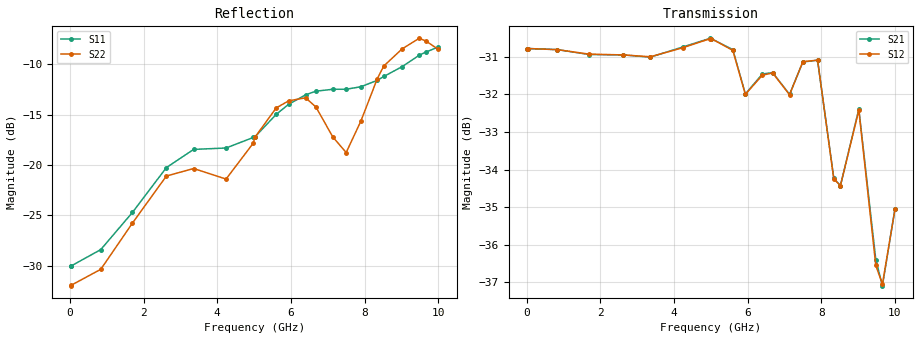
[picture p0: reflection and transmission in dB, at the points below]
! Integrated Device Technology
! Corporate Headquarters
! 6024 Silver Creek Valley Road
! San Jose, CA 95138  USA
! Phone:  1-408-284-8200
! Toll Free:  1-800-223-1366
! Webpage:  http://www.idt.com/
! Timing and RF Division
! 515 Groton Road, Suite 102
! Westford, MA 01886-6024
! Device:  F1958
! Description: 7-bit 0.25 dB Digital Step Attenuator
! Frequency:  0.001 -  6.000 GHz
! Package:  4x4 mm Thin QFN Plastic Package: 24 pin
! Ports:  2 RF, 12 DC
!  Pin  1  = D0
!  Pin  2  = VDD
!  Pin  3  = VMODE
!  Pin  4  = GND
!  Pin  5  = RF1  =  Port 1
!  Pin  6  = GND
!  Pin  7  = GND
!  Pin  8  = GND
!  Pin  9  = GND
!  Pin 10  = GND
!  Pin 11  = GND
!  Pin 12  = GND
!  Pin 13  = GND
!  Pin 14  = RF2  =  Port 2
!  Pin 15  = GND
!  Pin 16  = LE
!  Pin 17  = CLK
!  Pin 18  = DATA
!  Pin 19  = D6
!  Pin 20  = D5
!  Pin 21  = D4
!  Pin 22  = D3
!  Pin 23  = D2
!  Pin 24  = D1
! State:  120
! Atten State:  30.00 dB
! Voltage:  +3.30 Volts
! Current:  0.258 mA
! Data:  The device was measured on a F1958 evaluation board which has
!  individual transmission lines to the RF pins.  Data was collected
!  using a calibrated network analyzer.  The evaluation board was
!  de-embedded using Automatic Fixture Removal (AFR).
!  The reference plane is the edge of the package pin.
! Misc:
!  Action Tracker AT0419
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# GHz S dB R 50
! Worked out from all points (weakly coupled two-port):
!   500 points, 20 MHz to 10 GHz, reference 50 ohm
!   highest |S21| = -30.51 dB at 4.98 GHz (marker M1); lowest = -37.1 dB at 9.66 GHz (marker M2)
!   lowest |S11| = -30.0 dB at 40 MHz (marker M3), VSWR 1.07, Z = 46.9 - j0.0458 ohm
!   |S11| at or under -10 dB: start of sweep to 9.054 GHz
!   |S22| runs from -32.2 to -7.4 dB; largest |S21 - S12| = 0.00039
!   S11 on the Smith chart (normalised r, x): 20 MHz: 0.94, -0.00; 6.4 GHz: 0.67, +0.17; 10 GHz: 0.67, +0.60
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0.02  -30.01 -178.9  -30.80 -0.2  -30.80 -0.1  -32.00 -178.8
0.04  -30.03 -179.1  -30.78 -0.3  -30.78 -0.3  -31.95 -178.4
0.84  -28.41 171.8  -30.81 -9.4  -30.81 -9.4  -30.37 172.9
1.7  -24.71 171.9  -30.94 -18.5  -30.93 -18.5  -25.77 171.9
2.62  -20.26 177.6  -30.95 -28.4  -30.95 -28.4  -21.10 -179.1
3.36  -18.45 -175.3  -31.01 -36.8  -31.00 -37.0  -20.35 -169.2
4.24  -18.31 -178.8  -30.74 -46.2  -30.76 -46.3  -21.40 169.3
4.98  -17.26 162.1  -30.51 -55.4  -30.52 -55.4  -17.82 138.3
5.02  -17.22 161.1  -30.52 -56.2  -30.52 -56.2  -17.26 138.7
5.6  -14.97 151.1  -30.81 -64.8  -30.83 -64.8  -14.33 140.4
5.94  -13.96 148.5  -31.99 -68.4  -32.00 -68.4  -13.62 148.7
6.4  -13.02 147.9  -31.46 -73.6  -31.49 -73.5  -13.32 155.6
6.68  -12.66 146.7  -31.42 -76.1  -31.43 -76.1  -14.24 157.4
7.14  -12.47 142.7  -32.00 -81.2  -32.01 -81.1  -17.23 151.5
7.5  -12.47 138.2  -31.14 -84.7  -31.13 -84.6  -18.76 120.0
7.9  -12.22 128.8  -31.09 -100.4  -31.09 -100.5  -15.63 89.8
8.34  -11.59 118.8  -34.23 -106.0  -34.25 -106.1  -11.46 84.4
8.52  -11.20 115.5  -34.43 -97.5  -34.43 -97.7  -10.16 87.7
9.02  -10.22 107.6  -32.39 -106.7  -32.42 -106.5  -8.45 98.0
9.48  -9.09 101.6  -36.40 -112.2  -36.55 -111.9  -7.41 107.7
9.66  -8.78 100.5  -37.09 -100.3  -37.05 -100.5  -7.66 110.3
10  -8.27 99.5  -35.05 -86.7  -35.06 -86.5  -8.51 113.9
